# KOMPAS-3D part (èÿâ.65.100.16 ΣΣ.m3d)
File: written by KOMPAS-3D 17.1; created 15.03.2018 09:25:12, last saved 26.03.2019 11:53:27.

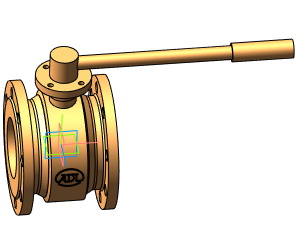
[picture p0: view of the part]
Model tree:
1. Операция без истории:3  (labels: Сталь 20  ГОСТ 1050-2013)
